VERSION 5.7 ;
  NOWIREEXTENSIONATPIN ON ;
  DIVIDERCHAR "/" ;
  BUSBITCHARS "[]" ;
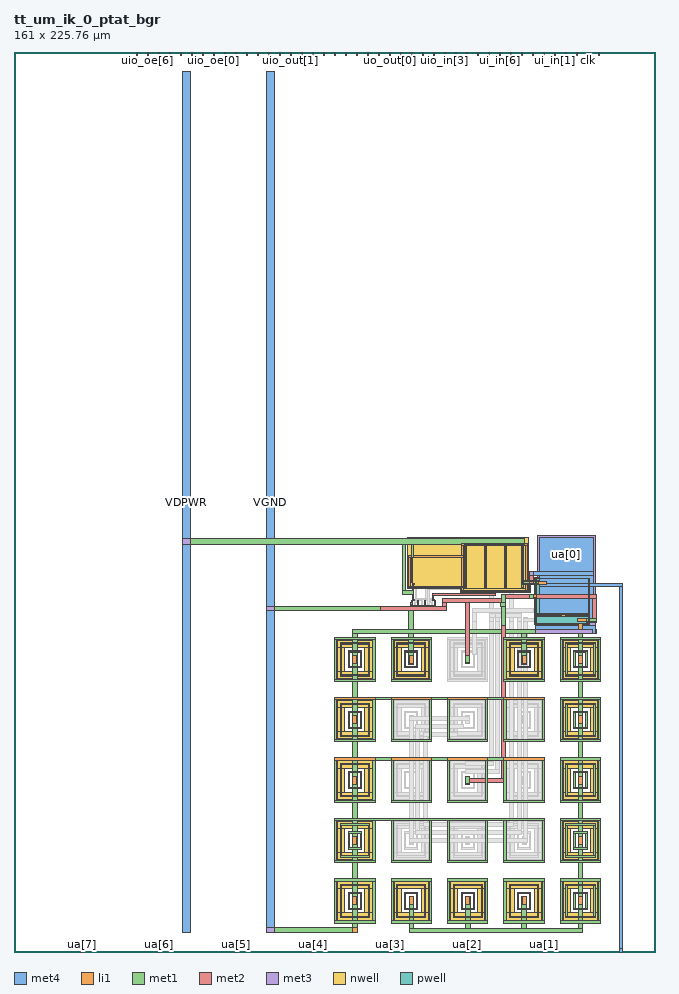
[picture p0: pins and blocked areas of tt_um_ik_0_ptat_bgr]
MACRO tt_um_ik_0_ptat_bgr
  CLASS BLOCK ;
  FOREIGN tt_um_ik_0_ptat_bgr ;
  ORIGIN 0.000 0.000 ;
  SIZE 161.000 BY 225.760 ;
  PIN clk
    DIRECTION INPUT ;
    USE SIGNAL ;
    PORT
      LAYER met4 ;
        RECT 143.830 224.760 144.130 225.760 ;
    END
  END clk
  PIN ena
    DIRECTION INPUT ;
    USE SIGNAL ;
    PORT
      LAYER met4 ;
        RECT 146.590 224.760 146.890 225.760 ;
    END
  END ena
  PIN rst_n
    DIRECTION INPUT ;
    USE SIGNAL ;
    PORT
      LAYER met4 ;
        RECT 141.070 224.760 141.370 225.760 ;
    END
  END rst_n
  PIN ua[0]
    DIRECTION INOUT ;
    USE SIGNAL ;
    ANTENNAGATEAREA 0.500000 ;
    ANTENNADIFFAREA 2.900000 ;
    PORT
      LAYER li1 ;
        RECT 127.530 91.580 127.700 101.620 ;
        RECT 131.540 92.310 133.700 93.000 ;
        RECT 104.890 88.320 105.390 88.490 ;
      LAYER met1 ;
        RECT 127.400 93.300 127.800 101.650 ;
        RECT 129.200 94.350 130.200 95.350 ;
        RECT 127.400 92.950 131.600 93.300 ;
        RECT 127.400 92.360 133.675 92.950 ;
        RECT 127.400 92.300 131.600 92.360 ;
        RECT 127.400 91.550 127.800 92.300 ;
        RECT 104.950 88.520 105.350 89.100 ;
        RECT 104.910 88.290 105.370 88.520 ;
      LAYER met2 ;
        RECT 129.200 92.300 130.200 95.350 ;
        RECT 129.200 90.550 129.600 92.300 ;
        RECT 120.350 90.150 129.600 90.550 ;
        RECT 120.350 89.900 120.750 90.150 ;
        RECT 104.950 89.500 120.750 89.900 ;
        RECT 104.950 88.600 105.350 89.500 ;
      LAYER met3 ;
        RECT 129.200 94.350 130.200 95.350 ;
      LAYER met4 ;
        RECT 131.745 95.350 145.355 103.965 ;
        RECT 129.200 94.350 145.355 95.350 ;
        RECT 131.745 92.500 145.355 94.350 ;
        RECT 131.745 91.600 152.700 92.500 ;
        RECT 131.745 83.355 145.355 91.600 ;
        RECT 151.800 1.000 152.700 91.600 ;
        RECT 151.800 0.000 152.710 1.000 ;
    END
  END ua[0]
  PIN ua[1]
    DIRECTION INOUT ;
    USE SIGNAL ;
    PORT
      LAYER met4 ;
        RECT 132.490 0.000 133.390 1.000 ;
    END
  END ua[1]
  PIN ua[2]
    DIRECTION INOUT ;
    USE SIGNAL ;
    PORT
      LAYER met4 ;
        RECT 113.170 0.000 114.070 1.000 ;
    END
  END ua[2]
  PIN ua[3]
    DIRECTION INOUT ;
    USE SIGNAL ;
    PORT
      LAYER met4 ;
        RECT 93.850 0.000 94.750 1.000 ;
    END
  END ua[3]
  PIN ua[4]
    DIRECTION INOUT ;
    USE SIGNAL ;
    PORT
      LAYER met4 ;
        RECT 74.530 0.000 75.430 1.000 ;
    END
  END ua[4]
  PIN ua[5]
    DIRECTION INOUT ;
    USE SIGNAL ;
    PORT
      LAYER met4 ;
        RECT 55.210 0.000 56.110 1.000 ;
    END
  END ua[5]
  PIN ua[6]
    DIRECTION INOUT ;
    USE SIGNAL ;
    PORT
      LAYER met4 ;
        RECT 35.890 0.000 36.790 1.000 ;
    END
  END ua[6]
  PIN ua[7]
    DIRECTION INOUT ;
    USE SIGNAL ;
    PORT
      LAYER met4 ;
        RECT 16.570 0.000 17.470 1.000 ;
    END
  END ua[7]
  PIN ui_in[0]
    DIRECTION INPUT ;
    USE SIGNAL ;
    PORT
      LAYER met4 ;
        RECT 138.310 224.760 138.610 225.760 ;
    END
  END ui_in[0]
  PIN ui_in[1]
    DIRECTION INPUT ;
    USE SIGNAL ;
    PORT
      LAYER met4 ;
        RECT 135.550 224.760 135.850 225.760 ;
    END
  END ui_in[1]
  PIN ui_in[2]
    DIRECTION INPUT ;
    USE SIGNAL ;
    PORT
      LAYER met4 ;
        RECT 132.790 224.760 133.090 225.760 ;
    END
  END ui_in[2]
  PIN ui_in[3]
    DIRECTION INPUT ;
    USE SIGNAL ;
    PORT
      LAYER met4 ;
        RECT 130.030 224.760 130.330 225.760 ;
    END
  END ui_in[3]
  PIN ui_in[4]
    DIRECTION INPUT ;
    USE SIGNAL ;
    PORT
      LAYER met4 ;
        RECT 127.270 224.760 127.570 225.760 ;
    END
  END ui_in[4]
  PIN ui_in[5]
    DIRECTION INPUT ;
    USE SIGNAL ;
    PORT
      LAYER met4 ;
        RECT 124.510 224.760 124.810 225.760 ;
    END
  END ui_in[5]
  PIN ui_in[6]
    DIRECTION INPUT ;
    USE SIGNAL ;
    PORT
      LAYER met4 ;
        RECT 121.750 224.760 122.050 225.760 ;
    END
  END ui_in[6]
  PIN ui_in[7]
    DIRECTION INPUT ;
    USE SIGNAL ;
    PORT
      LAYER met4 ;
        RECT 118.990 224.760 119.290 225.760 ;
    END
  END ui_in[7]
  PIN uio_in[0]
    DIRECTION INPUT ;
    USE SIGNAL ;
    PORT
      LAYER met4 ;
        RECT 116.230 224.760 116.530 225.760 ;
    END
  END uio_in[0]
  PIN uio_in[1]
    DIRECTION INPUT ;
    USE SIGNAL ;
    PORT
      LAYER met4 ;
        RECT 113.470 224.760 113.770 225.760 ;
    END
  END uio_in[1]
  PIN uio_in[2]
    DIRECTION INPUT ;
    USE SIGNAL ;
    PORT
      LAYER met4 ;
        RECT 110.710 224.760 111.010 225.760 ;
    END
  END uio_in[2]
  PIN uio_in[3]
    DIRECTION INPUT ;
    USE SIGNAL ;
    PORT
      LAYER met4 ;
        RECT 107.950 224.760 108.250 225.760 ;
    END
  END uio_in[3]
  PIN uio_in[4]
    DIRECTION INPUT ;
    USE SIGNAL ;
    PORT
      LAYER met4 ;
        RECT 105.190 224.760 105.490 225.760 ;
    END
  END uio_in[4]
  PIN uio_in[5]
    DIRECTION INPUT ;
    USE SIGNAL ;
    PORT
      LAYER met4 ;
        RECT 102.430 224.760 102.730 225.760 ;
    END
  END uio_in[5]
  PIN uio_in[6]
    DIRECTION INPUT ;
    USE SIGNAL ;
    PORT
      LAYER met4 ;
        RECT 99.670 224.760 99.970 225.760 ;
    END
  END uio_in[6]
  PIN uio_in[7]
    DIRECTION INPUT ;
    USE SIGNAL ;
    PORT
      LAYER met4 ;
        RECT 96.910 224.760 97.210 225.760 ;
    END
  END uio_in[7]
  PIN uio_oe[0]
    DIRECTION OUTPUT ;
    USE SIGNAL ;
    PORT
      LAYER met4 ;
        RECT 49.990 224.760 50.290 225.760 ;
    END
  END uio_oe[0]
  PIN uio_oe[1]
    DIRECTION OUTPUT ;
    USE SIGNAL ;
    PORT
      LAYER met4 ;
        RECT 47.230 224.760 47.530 225.760 ;
    END
  END uio_oe[1]
  PIN uio_oe[2]
    DIRECTION OUTPUT ;
    USE SIGNAL ;
    PORT
      LAYER met4 ;
        RECT 44.470 224.760 44.770 225.760 ;
    END
  END uio_oe[2]
  PIN uio_oe[3]
    DIRECTION OUTPUT ;
    USE SIGNAL ;
    PORT
      LAYER met4 ;
        RECT 41.710 224.760 42.010 225.760 ;
    END
  END uio_oe[3]
  PIN uio_oe[4]
    DIRECTION OUTPUT ;
    USE SIGNAL ;
    PORT
      LAYER met4 ;
        RECT 38.950 224.760 39.250 225.760 ;
    END
  END uio_oe[4]
  PIN uio_oe[5]
    DIRECTION OUTPUT ;
    USE SIGNAL ;
    PORT
      LAYER met4 ;
        RECT 36.190 224.760 36.490 225.760 ;
    END
  END uio_oe[5]
  PIN uio_oe[6]
    DIRECTION OUTPUT ;
    USE SIGNAL ;
    PORT
      LAYER met4 ;
        RECT 33.430 224.760 33.730 225.760 ;
    END
  END uio_oe[6]
  PIN uio_oe[7]
    DIRECTION OUTPUT ;
    USE SIGNAL ;
    PORT
      LAYER met4 ;
        RECT 30.670 224.760 30.970 225.760 ;
    END
  END uio_oe[7]
  PIN uio_out[0]
    DIRECTION OUTPUT ;
    USE SIGNAL ;
    PORT
      LAYER met4 ;
        RECT 72.070 224.760 72.370 225.760 ;
    END
  END uio_out[0]
  PIN uio_out[1]
    DIRECTION OUTPUT ;
    USE SIGNAL ;
    PORT
      LAYER met4 ;
        RECT 69.310 224.760 69.610 225.760 ;
    END
  END uio_out[1]
  PIN uio_out[2]
    DIRECTION OUTPUT ;
    USE SIGNAL ;
    PORT
      LAYER met4 ;
        RECT 66.550 224.760 66.850 225.760 ;
    END
  END uio_out[2]
  PIN uio_out[3]
    DIRECTION OUTPUT ;
    USE SIGNAL ;
    PORT
      LAYER met4 ;
        RECT 63.790 224.760 64.090 225.760 ;
    END
  END uio_out[3]
  PIN uio_out[4]
    DIRECTION OUTPUT ;
    USE SIGNAL ;
    PORT
      LAYER met4 ;
        RECT 61.030 224.760 61.330 225.760 ;
    END
  END uio_out[4]
  PIN uio_out[5]
    DIRECTION OUTPUT ;
    USE SIGNAL ;
    PORT
      LAYER met4 ;
        RECT 58.270 224.760 58.570 225.760 ;
    END
  END uio_out[5]
  PIN uio_out[6]
    DIRECTION OUTPUT ;
    USE SIGNAL ;
    PORT
      LAYER met4 ;
        RECT 55.510 224.760 55.810 225.760 ;
    END
  END uio_out[6]
  PIN uio_out[7]
    DIRECTION OUTPUT ;
    USE SIGNAL ;
    PORT
      LAYER met4 ;
        RECT 52.750 224.760 53.050 225.760 ;
    END
  END uio_out[7]
  PIN uo_out[0]
    DIRECTION OUTPUT ;
    USE SIGNAL ;
    PORT
      LAYER met4 ;
        RECT 94.150 224.760 94.450 225.760 ;
    END
  END uo_out[0]
  PIN uo_out[1]
    DIRECTION OUTPUT ;
    USE SIGNAL ;
    PORT
      LAYER met4 ;
        RECT 91.390 224.760 91.690 225.760 ;
    END
  END uo_out[1]
  PIN uo_out[2]
    DIRECTION OUTPUT ;
    USE SIGNAL ;
    PORT
      LAYER met4 ;
        RECT 88.630 224.760 88.930 225.760 ;
    END
  END uo_out[2]
  PIN uo_out[3]
    DIRECTION OUTPUT ;
    USE SIGNAL ;
    PORT
      LAYER met4 ;
        RECT 85.870 224.760 86.170 225.760 ;
    END
  END uo_out[3]
  PIN uo_out[4]
    DIRECTION OUTPUT ;
    USE SIGNAL ;
    PORT
      LAYER met4 ;
        RECT 83.110 224.760 83.410 225.760 ;
    END
  END uo_out[4]
  PIN uo_out[5]
    DIRECTION OUTPUT ;
    USE SIGNAL ;
    PORT
      LAYER met4 ;
        RECT 80.350 224.760 80.650 225.760 ;
    END
  END uo_out[5]
  PIN uo_out[6]
    DIRECTION OUTPUT ;
    USE SIGNAL ;
    PORT
      LAYER met4 ;
        RECT 77.590 224.760 77.890 225.760 ;
    END
  END uo_out[6]
  PIN uo_out[7]
    DIRECTION OUTPUT ;
    USE SIGNAL ;
    PORT
      LAYER met4 ;
        RECT 74.830 224.760 75.130 225.760 ;
    END
  END uo_out[7]
  PIN VDPWR
    DIRECTION INOUT ;
    USE POWER ;
    PORT
      LAYER nwell ;
        RECT 98.800 91.100 129.000 104.100 ;
        RECT 112.000 90.100 129.000 91.100 ;
      LAYER li1 ;
        RECT 112.300 102.000 128.700 102.400 ;
        RECT 112.300 99.400 112.700 102.000 ;
        RECT 99.000 99.000 112.700 99.400 ;
        RECT 99.000 91.800 99.400 99.000 ;
        RECT 99.840 97.080 100.010 98.120 ;
        RECT 99.740 92.680 99.910 93.720 ;
        RECT 99.970 92.295 100.470 92.465 ;
        RECT 112.300 91.800 112.700 99.000 ;
        RECT 99.000 91.400 112.700 91.800 ;
        RECT 113.240 91.580 113.410 101.620 ;
        RECT 118.240 91.580 118.410 101.620 ;
        RECT 123.240 91.580 123.410 101.620 ;
        RECT 112.300 90.800 112.700 91.400 ;
        RECT 128.300 90.800 128.700 102.000 ;
        RECT 112.300 90.400 128.700 90.800 ;
        RECT 99.940 88.320 100.440 88.490 ;
      LAYER met1 ;
        RECT 42.200 102.100 128.000 103.600 ;
        RECT 97.400 90.700 98.200 102.100 ;
        RECT 99.600 98.900 100.150 102.100 ;
        RECT 113.000 102.000 128.000 102.100 ;
        RECT 99.700 97.100 100.050 98.900 ;
        RECT 99.700 93.700 99.900 97.100 ;
        RECT 99.700 93.650 99.940 93.700 ;
        RECT 99.710 92.700 99.940 93.650 ;
        RECT 99.990 92.265 100.450 92.495 ;
        RECT 100.000 90.700 100.250 92.265 ;
        RECT 113.100 91.550 113.500 102.000 ;
        RECT 118.100 91.550 118.500 102.000 ;
        RECT 123.100 91.550 123.500 102.000 ;
        RECT 97.400 89.700 100.250 90.700 ;
        RECT 100.000 88.520 100.250 89.700 ;
        RECT 99.960 88.290 100.420 88.520 ;
      LAYER met2 ;
        RECT 42.200 102.100 44.200 103.600 ;
      LAYER met3 ;
        RECT 42.200 102.100 44.200 103.600 ;
      LAYER met4 ;
        RECT 42.200 5.000 44.200 220.760 ;
    END
  END VDPWR
  PIN VGND
    DIRECTION INOUT ;
    USE GROUND ;
    PORT
      LAYER pwell ;
        RECT 130.600 84.400 144.600 94.000 ;
        RECT 130.600 82.100 144.420 84.400 ;
      LAYER nwell ;
        RECT 81.200 76.420 89.820 78.220 ;
        RECT 81.200 70.400 83.000 76.420 ;
        RECT 88.020 70.400 89.820 76.420 ;
        RECT 81.200 68.600 89.820 70.400 ;
        RECT 95.350 76.420 103.970 78.220 ;
        RECT 95.350 70.400 97.150 76.420 ;
        RECT 102.170 70.400 103.970 76.420 ;
        RECT 95.350 68.600 103.970 70.400 ;
        RECT 123.650 76.420 132.270 78.220 ;
        RECT 123.650 70.400 125.450 76.420 ;
        RECT 130.470 70.400 132.270 76.420 ;
        RECT 123.650 68.600 132.270 70.400 ;
        RECT 137.800 76.420 146.420 78.220 ;
        RECT 137.800 70.400 139.600 76.420 ;
        RECT 144.620 70.400 146.420 76.420 ;
        RECT 137.800 68.600 146.420 70.400 ;
        RECT 81.200 61.270 89.820 63.070 ;
        RECT 81.200 55.250 83.000 61.270 ;
        RECT 88.020 55.250 89.820 61.270 ;
        RECT 81.200 53.450 89.820 55.250 ;
        RECT 137.800 61.270 146.420 63.070 ;
        RECT 137.800 55.250 139.600 61.270 ;
        RECT 144.620 55.250 146.420 61.270 ;
        RECT 137.800 53.450 146.420 55.250 ;
        RECT 81.200 46.120 89.820 47.920 ;
        RECT 81.200 40.100 83.000 46.120 ;
        RECT 88.020 40.100 89.820 46.120 ;
        RECT 81.200 38.300 89.820 40.100 ;
        RECT 137.800 46.120 146.420 47.920 ;
        RECT 137.800 40.100 139.600 46.120 ;
        RECT 144.620 40.100 146.420 46.120 ;
        RECT 137.800 38.300 146.420 40.100 ;
        RECT 81.200 30.970 89.820 32.770 ;
        RECT 81.200 24.950 83.000 30.970 ;
        RECT 88.020 24.950 89.820 30.970 ;
        RECT 81.200 23.150 89.820 24.950 ;
        RECT 137.800 30.970 146.420 32.770 ;
        RECT 137.800 24.950 139.600 30.970 ;
        RECT 144.620 24.950 146.420 30.970 ;
        RECT 137.800 23.150 146.420 24.950 ;
        RECT 81.200 15.820 89.820 17.620 ;
        RECT 81.200 9.800 83.000 15.820 ;
        RECT 88.020 9.800 89.820 15.820 ;
        RECT 81.200 8.000 89.820 9.800 ;
        RECT 95.350 15.820 103.970 17.620 ;
        RECT 95.350 9.800 97.150 15.820 ;
        RECT 102.170 9.800 103.970 15.820 ;
        RECT 95.350 8.000 103.970 9.800 ;
        RECT 109.500 15.820 118.120 17.620 ;
        RECT 109.500 9.800 111.300 15.820 ;
        RECT 116.320 9.800 118.120 15.820 ;
        RECT 109.500 8.000 118.120 9.800 ;
        RECT 123.650 15.820 132.270 17.620 ;
        RECT 123.650 9.800 125.450 15.820 ;
        RECT 130.470 9.800 132.270 15.820 ;
        RECT 123.650 8.000 132.270 9.800 ;
        RECT 137.800 15.820 146.420 17.620 ;
        RECT 137.800 9.800 139.600 15.820 ;
        RECT 144.620 9.800 146.420 15.820 ;
        RECT 137.800 8.000 146.420 9.800 ;
      LAYER li1 ;
        RECT 130.800 93.600 144.400 93.800 ;
        RECT 130.800 89.600 131.000 93.600 ;
        RECT 130.400 88.800 131.000 89.600 ;
        RECT 99.710 87.110 99.880 88.150 ;
        RECT 101.360 87.110 101.530 88.150 ;
        RECT 103.010 87.110 103.180 88.150 ;
        RECT 105.450 87.110 105.620 88.150 ;
        RECT 130.800 84.800 131.000 88.800 ;
        RECT 144.200 84.800 144.400 93.600 ;
        RECT 130.800 84.600 144.400 84.800 ;
        RECT 137.300 84.270 138.300 84.600 ;
        RECT 130.780 84.100 144.240 84.270 ;
        RECT 130.780 82.450 130.950 84.100 ;
        RECT 141.430 82.930 143.590 83.620 ;
        RECT 144.070 82.450 144.240 84.100 ;
        RECT 130.780 82.280 144.240 82.450 ;
        RECT 141.600 80.850 142.600 82.280 ;
        RECT 80.400 78.400 90.600 79.000 ;
        RECT 80.400 68.400 81.000 78.400 ;
        RECT 81.830 77.260 89.190 77.590 ;
        RECT 81.830 69.560 82.160 77.260 ;
        RECT 83.840 75.250 87.180 75.580 ;
        RECT 83.840 71.570 84.170 75.250 ;
        RECT 85.005 72.395 86.015 74.425 ;
        RECT 86.850 71.570 87.180 75.250 ;
        RECT 83.840 71.240 87.180 71.570 ;
        RECT 88.860 69.560 89.190 77.260 ;
        RECT 81.830 69.230 89.190 69.560 ;
        RECT 90.000 68.400 90.600 78.400 ;
        RECT 80.400 67.800 90.600 68.400 ;
        RECT 94.600 78.400 104.800 79.000 ;
        RECT 94.600 68.400 95.200 78.400 ;
        RECT 95.980 77.260 103.340 77.590 ;
        RECT 95.980 69.560 96.310 77.260 ;
        RECT 97.990 75.250 101.330 75.580 ;
        RECT 97.990 71.570 98.320 75.250 ;
        RECT 99.155 72.395 100.165 74.425 ;
        RECT 101.000 71.570 101.330 75.250 ;
        RECT 97.990 71.240 101.330 71.570 ;
        RECT 103.010 69.560 103.340 77.260 ;
        RECT 95.980 69.230 103.340 69.560 ;
        RECT 104.200 68.400 104.800 78.400 ;
        RECT 122.900 78.400 133.100 79.000 ;
        RECT 113.305 72.395 114.315 74.425 ;
        RECT 94.600 67.800 104.800 68.400 ;
        RECT 122.900 68.400 123.500 78.400 ;
        RECT 124.280 77.260 131.640 77.590 ;
        RECT 124.280 69.560 124.610 77.260 ;
        RECT 126.290 75.250 129.630 75.580 ;
        RECT 126.290 71.570 126.620 75.250 ;
        RECT 127.455 72.395 128.465 74.425 ;
        RECT 129.300 71.570 129.630 75.250 ;
        RECT 126.290 71.240 129.630 71.570 ;
        RECT 131.310 69.560 131.640 77.260 ;
        RECT 124.280 69.230 131.640 69.560 ;
        RECT 132.500 68.400 133.100 78.400 ;
        RECT 122.900 67.800 133.100 68.400 ;
        RECT 137.000 78.400 147.200 79.000 ;
        RECT 137.000 68.400 137.600 78.400 ;
        RECT 138.430 77.260 145.790 77.590 ;
        RECT 138.430 69.560 138.760 77.260 ;
        RECT 140.440 75.250 143.780 75.580 ;
        RECT 140.440 71.570 140.770 75.250 ;
        RECT 141.605 72.395 142.615 74.425 ;
        RECT 143.450 71.570 143.780 75.250 ;
        RECT 140.440 71.240 143.780 71.570 ;
        RECT 145.460 69.560 145.790 77.260 ;
        RECT 138.430 69.230 145.790 69.560 ;
        RECT 146.600 68.400 147.200 78.400 ;
        RECT 137.000 67.800 147.200 68.400 ;
        RECT 80.400 63.300 90.600 63.900 ;
        RECT 80.400 53.300 81.000 63.300 ;
        RECT 81.830 62.110 89.190 62.440 ;
        RECT 81.830 54.410 82.160 62.110 ;
        RECT 83.840 60.100 87.180 60.430 ;
        RECT 83.840 56.420 84.170 60.100 ;
        RECT 85.005 57.245 86.015 59.275 ;
        RECT 86.850 56.420 87.180 60.100 ;
        RECT 83.840 56.090 87.180 56.420 ;
        RECT 88.860 54.410 89.190 62.110 ;
        RECT 81.830 54.080 89.190 54.410 ;
        RECT 90.000 53.300 90.600 63.300 ;
        RECT 80.400 52.700 90.600 53.300 ;
        RECT 94.600 63.300 104.800 63.900 ;
        RECT 94.600 53.300 95.200 63.300 ;
        RECT 104.200 53.300 104.800 63.300 ;
        RECT 94.600 52.700 104.800 53.300 ;
        RECT 108.700 63.300 118.900 63.900 ;
        RECT 108.700 53.300 109.300 63.300 ;
        RECT 118.300 53.300 118.900 63.300 ;
        RECT 108.700 52.700 118.900 53.300 ;
        RECT 122.900 63.300 133.100 63.900 ;
        RECT 122.900 53.300 123.500 63.300 ;
        RECT 132.500 53.300 133.100 63.300 ;
        RECT 122.900 52.700 133.100 53.300 ;
        RECT 137.000 63.300 147.200 63.900 ;
        RECT 137.000 53.300 137.600 63.300 ;
        RECT 138.430 62.110 145.790 62.440 ;
        RECT 138.430 54.410 138.760 62.110 ;
        RECT 140.440 60.100 143.780 60.430 ;
        RECT 140.440 56.420 140.770 60.100 ;
        RECT 141.605 57.245 142.615 59.275 ;
        RECT 143.450 56.420 143.780 60.100 ;
        RECT 140.440 56.090 143.780 56.420 ;
        RECT 145.460 54.410 145.790 62.110 ;
        RECT 138.430 54.080 145.790 54.410 ;
        RECT 146.600 53.300 147.200 63.300 ;
        RECT 137.000 52.700 147.200 53.300 ;
        RECT 80.400 48.100 90.600 48.700 ;
        RECT 80.400 38.100 81.000 48.100 ;
        RECT 81.830 46.960 89.190 47.290 ;
        RECT 81.830 39.260 82.160 46.960 ;
        RECT 83.840 44.950 87.180 45.280 ;
        RECT 83.840 41.270 84.170 44.950 ;
        RECT 85.005 42.095 86.015 44.125 ;
        RECT 86.850 41.270 87.180 44.950 ;
        RECT 83.840 40.940 87.180 41.270 ;
        RECT 88.860 39.260 89.190 46.960 ;
        RECT 81.830 38.930 89.190 39.260 ;
        RECT 90.000 38.100 90.600 48.100 ;
        RECT 80.400 37.500 90.600 38.100 ;
        RECT 94.600 48.100 104.800 48.700 ;
        RECT 94.600 38.100 95.200 48.100 ;
        RECT 104.200 38.100 104.800 48.100 ;
        RECT 94.600 37.500 104.800 38.100 ;
        RECT 108.700 48.100 118.900 48.700 ;
        RECT 108.700 38.100 109.300 48.100 ;
        RECT 113.305 42.095 114.315 44.125 ;
        RECT 118.300 38.100 118.900 48.100 ;
        RECT 108.700 37.500 118.900 38.100 ;
        RECT 122.900 48.100 133.100 48.700 ;
        RECT 122.900 38.100 123.500 48.100 ;
        RECT 132.500 38.100 133.100 48.100 ;
        RECT 122.900 37.500 133.100 38.100 ;
        RECT 137.000 48.100 147.200 48.700 ;
        RECT 137.000 38.100 137.600 48.100 ;
        RECT 138.430 46.960 145.790 47.290 ;
        RECT 138.430 39.260 138.760 46.960 ;
        RECT 140.440 44.950 143.780 45.280 ;
        RECT 140.440 41.270 140.770 44.950 ;
        RECT 141.605 42.095 142.615 44.125 ;
        RECT 143.450 41.270 143.780 44.950 ;
        RECT 140.440 40.940 143.780 41.270 ;
        RECT 145.460 39.260 145.790 46.960 ;
        RECT 138.430 38.930 145.790 39.260 ;
        RECT 146.600 38.100 147.200 48.100 ;
        RECT 137.000 37.500 147.200 38.100 ;
        RECT 80.400 33.000 133.100 33.600 ;
        RECT 80.400 23.000 81.000 33.000 ;
        RECT 81.830 31.810 89.190 32.140 ;
        RECT 81.830 24.110 82.160 31.810 ;
        RECT 83.840 29.800 87.180 30.130 ;
        RECT 83.840 26.120 84.170 29.800 ;
        RECT 85.005 26.945 86.015 28.975 ;
        RECT 86.850 26.120 87.180 29.800 ;
        RECT 83.840 25.790 87.180 26.120 ;
        RECT 88.860 24.110 89.190 31.810 ;
        RECT 81.830 23.780 89.190 24.110 ;
        RECT 90.000 23.000 90.600 33.000 ;
        RECT 80.400 22.400 90.600 23.000 ;
        RECT 94.600 23.000 95.200 33.000 ;
        RECT 104.200 23.000 104.800 33.000 ;
        RECT 94.600 22.400 104.800 23.000 ;
        RECT 108.700 23.000 109.300 33.000 ;
        RECT 118.300 23.000 118.900 33.000 ;
        RECT 108.700 22.400 118.900 23.000 ;
        RECT 122.900 23.000 123.500 33.000 ;
        RECT 132.500 23.000 133.100 33.000 ;
        RECT 122.900 22.400 133.100 23.000 ;
        RECT 137.000 33.000 147.200 33.600 ;
        RECT 137.000 23.000 137.600 33.000 ;
        RECT 138.430 31.810 145.790 32.140 ;
        RECT 138.430 24.110 138.760 31.810 ;
        RECT 140.440 29.800 143.780 30.130 ;
        RECT 140.440 26.120 140.770 29.800 ;
        RECT 141.605 26.945 142.615 28.975 ;
        RECT 143.450 26.120 143.780 29.800 ;
        RECT 140.440 25.790 143.780 26.120 ;
        RECT 145.460 24.110 145.790 31.810 ;
        RECT 138.430 23.780 145.790 24.110 ;
        RECT 146.600 23.000 147.200 33.000 ;
        RECT 137.000 22.400 147.200 23.000 ;
        RECT 80.400 17.800 90.600 18.400 ;
        RECT 80.400 7.800 81.000 17.800 ;
        RECT 81.830 16.660 89.190 16.990 ;
        RECT 81.830 8.960 82.160 16.660 ;
        RECT 83.840 14.650 87.180 14.980 ;
        RECT 83.840 10.970 84.170 14.650 ;
        RECT 85.005 11.795 86.015 13.825 ;
        RECT 86.850 10.970 87.180 14.650 ;
        RECT 83.840 10.640 87.180 10.970 ;
        RECT 88.860 8.960 89.190 16.660 ;
        RECT 81.830 8.630 89.190 8.960 ;
        RECT 90.000 7.800 90.600 17.800 ;
        RECT 80.400 7.200 90.600 7.800 ;
        RECT 94.600 17.800 104.800 18.400 ;
        RECT 94.600 7.800 95.200 17.800 ;
        RECT 95.980 16.660 103.340 16.990 ;
        RECT 95.980 8.960 96.310 16.660 ;
        RECT 97.990 14.650 101.330 14.980 ;
        RECT 97.990 10.970 98.320 14.650 ;
        RECT 99.155 11.795 100.165 13.825 ;
        RECT 101.000 10.970 101.330 14.650 ;
        RECT 97.990 10.640 101.330 10.970 ;
        RECT 103.010 8.960 103.340 16.660 ;
        RECT 95.980 8.630 103.340 8.960 ;
        RECT 104.200 7.800 104.800 17.800 ;
        RECT 94.600 7.200 104.800 7.800 ;
        RECT 108.700 17.800 118.900 18.400 ;
        RECT 108.700 7.800 109.300 17.800 ;
        RECT 110.130 16.660 117.490 16.990 ;
        RECT 110.130 8.960 110.460 16.660 ;
        RECT 112.140 14.650 115.480 14.980 ;
        RECT 112.140 10.970 112.470 14.650 ;
        RECT 113.305 11.795 114.315 13.825 ;
        RECT 115.150 10.970 115.480 14.650 ;
        RECT 112.140 10.640 115.480 10.970 ;
        RECT 117.160 8.960 117.490 16.660 ;
        RECT 110.130 8.630 117.490 8.960 ;
        RECT 118.300 7.800 118.900 17.800 ;
        RECT 108.700 7.200 118.900 7.800 ;
        RECT 122.900 17.800 133.100 18.400 ;
        RECT 122.900 7.800 123.500 17.800 ;
        RECT 124.280 16.660 131.640 16.990 ;
        RECT 124.280 8.960 124.610 16.660 ;
        RECT 126.290 14.650 129.630 14.980 ;
        RECT 126.290 10.970 126.620 14.650 ;
        RECT 127.455 11.795 128.465 13.825 ;
        RECT 129.300 10.970 129.630 14.650 ;
        RECT 126.290 10.640 129.630 10.970 ;
        RECT 131.310 8.960 131.640 16.660 ;
        RECT 124.280 8.630 131.640 8.960 ;
        RECT 132.500 7.800 133.100 17.800 ;
        RECT 122.900 7.200 133.100 7.800 ;
        RECT 137.000 17.800 147.200 18.400 ;
        RECT 137.000 7.800 137.600 17.800 ;
        RECT 138.430 16.660 145.790 16.990 ;
        RECT 138.430 8.960 138.760 16.660 ;
        RECT 140.440 14.650 143.780 14.980 ;
        RECT 140.440 10.970 140.770 14.650 ;
        RECT 141.605 11.795 142.615 13.825 ;
        RECT 143.450 10.970 143.780 14.650 ;
        RECT 140.440 10.640 143.780 10.970 ;
        RECT 145.460 8.960 145.790 16.660 ;
        RECT 138.430 8.630 145.790 8.960 ;
        RECT 146.600 7.800 147.200 17.800 ;
        RECT 137.000 7.200 147.200 7.800 ;
        RECT 84.900 5.000 86.100 6.100 ;
      LAYER met1 ;
        RECT 99.680 87.550 99.910 88.130 ;
        RECT 101.330 87.550 101.560 88.130 ;
        RECT 102.980 87.550 103.210 88.130 ;
        RECT 99.550 87.130 99.910 87.550 ;
        RECT 101.200 87.130 101.560 87.550 ;
        RECT 102.850 87.130 103.210 87.550 ;
        RECT 105.420 87.550 105.650 88.130 ;
        RECT 122.200 87.600 123.200 89.700 ;
        RECT 129.200 88.700 131.000 89.700 ;
        RECT 105.420 87.130 105.800 87.550 ;
        RECT 99.550 86.850 99.800 87.130 ;
        RECT 101.200 86.850 101.450 87.130 ;
        RECT 102.850 86.850 103.100 87.130 ;
        RECT 105.550 86.850 105.800 87.130 ;
        RECT 99.550 86.700 105.800 86.850 ;
        RECT 63.300 85.700 105.800 86.700 ;
        RECT 122.000 86.600 123.200 87.600 ;
        RECT 99.000 81.000 100.250 85.700 ;
        RECT 122.200 81.800 123.200 86.600 ;
        RECT 143.500 83.570 146.150 83.750 ;
        RECT 141.455 82.980 146.150 83.570 ;
        RECT 143.500 82.750 146.150 82.980 ;
        RECT 84.900 80.000 146.150 81.000 ;
        RECT 84.900 79.000 86.100 80.000 ;
        RECT 99.000 79.000 100.250 80.000 ;
        RECT 127.400 79.000 128.600 80.000 ;
        RECT 141.490 79.990 142.700 80.000 ;
        RECT 141.500 79.000 142.700 79.990 ;
        RECT 80.400 78.400 90.600 79.000 ;
        RECT 80.400 68.400 81.000 78.400 ;
        RECT 84.900 77.570 86.100 78.400 ;
        RECT 81.850 77.280 89.170 77.570 ;
        RECT 81.850 69.540 82.140 77.280 ;
        RECT 84.900 75.560 86.100 77.280 ;
        RECT 83.860 75.270 87.160 75.560 ;
        RECT 83.860 71.550 84.150 75.270 ;
        RECT 84.900 71.550 86.100 75.270 ;
        RECT 86.870 71.550 87.160 75.270 ;
        RECT 83.860 71.260 87.160 71.550 ;
        RECT 84.900 69.540 86.100 71.260 ;
        RECT 88.880 69.540 89.170 77.280 ;
        RECT 81.850 69.250 89.170 69.540 ;
        RECT 84.900 68.400 86.100 69.250 ;
        RECT 90.000 68.400 90.600 78.400 ;
        RECT 80.400 67.800 90.600 68.400 ;
        RECT 94.600 78.400 104.800 79.000 ;
        RECT 94.600 68.400 95.200 78.400 ;
        RECT 99.000 77.570 100.250 78.400 ;
        RECT 96.000 77.280 103.320 77.570 ;
        RECT 96.000 69.540 96.290 77.280 ;
        RECT 99.000 75.560 100.250 77.280 ;
        RECT 98.010 75.270 101.310 75.560 ;
        RECT 98.010 71.550 98.300 75.270 ;
        RECT 99.000 72.100 100.250 75.270 ;
        RECT 101.020 71.550 101.310 75.270 ;
        RECT 98.010 71.260 101.310 71.550 ;
        RECT 103.030 69.540 103.320 77.280 ;
        RECT 96.000 69.250 103.320 69.540 ;
        RECT 104.200 68.400 104.800 78.400 ;
        RECT 122.900 78.400 133.100 79.000 ;
        RECT 113.305 72.545 114.315 74.275 ;
        RECT 94.600 67.800 104.800 68.400 ;
        RECT 122.900 68.400 123.500 78.400 ;
        RECT 127.400 77.570 128.600 78.400 ;
        RECT 124.300 77.280 131.620 77.570 ;
        RECT 124.300 69.540 124.590 77.280 ;
        RECT 127.400 75.560 128.600 77.280 ;
        RECT 126.310 75.270 129.610 75.560 ;
        RECT 126.310 71.550 126.600 75.270 ;
        RECT 127.400 72.100 128.600 75.270 ;
        RECT 129.320 71.550 129.610 75.270 ;
        RECT 126.310 71.260 129.610 71.550 ;
        RECT 131.330 69.540 131.620 77.280 ;
        RECT 124.300 69.250 131.620 69.540 ;
        RECT 132.500 68.400 133.100 78.400 ;
        RECT 122.900 67.800 133.100 68.400 ;
        RECT 137.000 78.400 147.200 79.000 ;
        RECT 137.000 68.400 137.600 78.400 ;
        RECT 141.500 77.570 142.700 78.400 ;
        RECT 138.450 77.280 145.770 77.570 ;
        RECT 138.450 69.540 138.740 77.280 ;
        RECT 141.500 75.560 142.700 77.280 ;
        RECT 140.460 75.270 143.760 75.560 ;
        RECT 140.460 71.550 140.750 75.270 ;
        RECT 141.500 71.550 142.700 75.270 ;
        RECT 143.470 71.550 143.760 75.270 ;
        RECT 140.460 71.260 143.760 71.550 ;
        RECT 141.500 69.540 142.700 71.260 ;
        RECT 145.480 69.540 145.770 77.280 ;
        RECT 138.450 69.250 145.770 69.540 ;
        RECT 141.500 68.400 142.700 69.250 ;
        RECT 146.600 68.400 147.200 78.400 ;
        RECT 137.000 67.800 147.200 68.400 ;
        RECT 84.900 63.900 86.100 67.800 ;
        RECT 141.500 63.900 142.700 67.800 ;
        RECT 80.400 63.300 133.100 63.900 ;
        RECT 80.400 53.300 81.000 63.300 ;
        RECT 84.900 62.420 86.100 63.300 ;
        RECT 81.850 62.130 89.170 62.420 ;
        RECT 81.850 54.390 82.140 62.130 ;
        RECT 84.900 60.410 86.100 62.130 ;
        RECT 83.860 60.120 87.160 60.410 ;
        RECT 83.860 56.400 84.150 60.120 ;
        RECT 84.900 56.400 86.100 60.120 ;
        RECT 86.870 56.400 87.160 60.120 ;
        RECT 83.860 56.110 87.160 56.400 ;
        RECT 84.900 54.390 86.100 56.110 ;
        RECT 88.880 54.390 89.170 62.130 ;
        RECT 81.850 54.100 89.170 54.390 ;
        RECT 84.900 53.300 86.100 54.100 ;
        RECT 90.000 53.300 90.600 63.300 ;
        RECT 80.400 52.700 90.600 53.300 ;
        RECT 94.600 53.300 95.200 63.300 ;
        RECT 104.200 53.300 104.800 63.300 ;
        RECT 94.600 52.700 104.800 53.300 ;
        RECT 108.700 53.300 109.300 63.300 ;
        RECT 118.300 53.300 118.900 63.300 ;
        RECT 108.700 52.700 118.900 53.300 ;
        RECT 122.900 53.300 123.500 63.300 ;
        RECT 132.500 53.300 133.100 63.300 ;
        RECT 122.900 52.700 133.100 53.300 ;
        RECT 137.000 63.300 147.200 63.900 ;
        RECT 137.000 53.300 137.600 63.300 ;
        RECT 141.500 62.420 142.700 63.300 ;
        RECT 138.450 62.130 145.770 62.420 ;
        RECT 138.450 54.390 138.740 62.130 ;
        RECT 141.500 60.410 142.700 62.130 ;
        RECT 140.460 60.120 143.760 60.410 ;
        RECT 140.460 56.400 140.750 60.120 ;
        RECT 141.500 56.400 142.700 60.120 ;
        RECT 143.470 56.400 143.760 60.120 ;
        RECT 140.460 56.110 143.760 56.400 ;
        RECT 141.500 54.390 142.700 56.110 ;
        RECT 145.480 54.390 145.770 62.130 ;
        RECT 138.450 54.100 145.770 54.390 ;
        RECT 141.500 53.300 142.700 54.100 ;
        RECT 146.600 53.300 147.200 63.300 ;
        RECT 137.000 52.700 147.200 53.300 ;
        RECT 84.900 48.700 86.100 52.700 ;
        RECT 141.500 48.700 142.700 52.700 ;
        RECT 80.400 48.100 133.100 48.700 ;
        RECT 80.400 38.100 81.000 48.100 ;
        RECT 84.900 47.270 86.100 48.100 ;
        RECT 81.850 46.980 89.170 47.270 ;
        RECT 81.850 39.240 82.140 46.980 ;
        RECT 84.900 45.260 86.100 46.980 ;
        RECT 83.860 44.970 87.160 45.260 ;
        RECT 83.860 41.250 84.150 44.970 ;
        RECT 84.900 41.250 86.100 44.970 ;
        RECT 86.870 41.250 87.160 44.970 ;
        RECT 83.860 40.960 87.160 41.250 ;
        RECT 84.900 39.240 86.100 40.960 ;
        RECT 88.880 39.240 89.170 46.980 ;
        RECT 81.850 38.950 89.170 39.240 ;
        RECT 84.900 38.100 86.100 38.950 ;
        RECT 90.000 38.100 90.600 48.100 ;
        RECT 80.400 37.500 90.600 38.100 ;
        RECT 94.600 38.100 95.200 48.100 ;
        RECT 104.200 38.100 104.800 48.100 ;
        RECT 94.600 37.500 104.800 38.100 ;
        RECT 108.700 38.100 109.300 48.100 ;
        RECT 113.305 42.245 114.315 43.975 ;
        RECT 118.300 38.100 118.900 48.100 ;
        RECT 108.700 37.500 118.900 38.100 ;
        RECT 122.900 38.100 123.500 48.100 ;
        RECT 132.500 38.100 133.100 48.100 ;
        RECT 122.900 37.500 133.100 38.100 ;
        RECT 137.000 48.100 147.200 48.700 ;
        RECT 137.000 38.100 137.600 48.100 ;
        RECT 141.500 47.270 142.700 48.100 ;
        RECT 138.450 46.980 145.770 47.270 ;
        RECT 138.450 39.240 138.740 46.980 ;
        RECT 141.500 45.260 142.700 46.980 ;
        RECT 140.460 44.970 143.760 45.260 ;
        RECT 140.460 41.250 140.750 44.970 ;
        RECT 141.500 41.250 142.700 44.970 ;
        RECT 143.470 41.250 143.760 44.970 ;
        RECT 140.460 40.960 143.760 41.250 ;
        RECT 141.500 39.240 142.700 40.960 ;
        RECT 145.480 39.240 145.770 46.980 ;
        RECT 138.450 38.950 145.770 39.240 ;
        RECT 141.500 38.100 142.700 38.950 ;
        RECT 146.600 38.100 147.200 48.100 ;
        RECT 137.000 37.500 147.200 38.100 ;
        RECT 84.900 33.600 86.100 37.500 ;
        RECT 141.500 33.600 142.700 37.500 ;
        RECT 80.400 33.000 133.100 33.600 ;
        RECT 80.400 23.000 81.000 33.000 ;
        RECT 84.900 32.120 86.100 33.000 ;
        RECT 81.850 31.830 89.170 32.120 ;
        RECT 81.850 24.090 82.140 31.830 ;
        RECT 84.900 30.110 86.100 31.830 ;
        RECT 83.860 29.820 87.160 30.110 ;
        RECT 83.860 26.100 84.150 29.820 ;
        RECT 84.900 26.100 86.100 29.820 ;
        RECT 86.870 26.100 87.160 29.820 ;
        RECT 83.860 25.810 87.160 26.100 ;
        RECT 84.900 24.090 86.100 25.810 ;
        RECT 88.880 24.090 89.170 31.830 ;
        RECT 81.850 23.800 89.170 24.090 ;
        RECT 84.900 23.000 86.100 23.800 ;
        RECT 90.000 23.000 90.600 33.000 ;
        RECT 80.400 22.400 90.600 23.000 ;
        RECT 94.600 23.000 95.200 33.000 ;
        RECT 104.200 23.000 104.800 33.000 ;
        RECT 94.600 22.400 104.800 23.000 ;
        RECT 108.700 23.000 109.300 33.000 ;
        RECT 118.300 23.000 118.900 33.000 ;
        RECT 108.700 22.400 118.900 23.000 ;
        RECT 122.900 23.000 123.500 33.000 ;
        RECT 132.500 23.000 133.100 33.000 ;
        RECT 122.900 22.400 133.100 23.000 ;
        RECT 137.000 33.000 147.200 33.600 ;
        RECT 137.000 23.000 137.600 33.000 ;
        RECT 141.500 32.120 142.700 33.000 ;
        RECT 138.450 31.830 145.770 32.120 ;
        RECT 138.450 24.090 138.740 31.830 ;
        RECT 141.500 30.110 142.700 31.830 ;
        RECT 140.460 29.820 143.760 30.110 ;
        RECT 140.460 26.100 140.750 29.820 ;
        RECT 141.500 26.100 142.700 29.820 ;
        RECT 143.470 26.100 143.760 29.820 ;
        RECT 140.460 25.810 143.760 26.100 ;
        RECT 141.500 24.090 142.700 25.810 ;
        RECT 145.480 24.090 145.770 31.830 ;
        RECT 138.450 23.800 145.770 24.090 ;
        RECT 141.500 23.000 142.700 23.800 ;
        RECT 146.600 23.000 147.200 33.000 ;
        RECT 137.000 22.400 147.200 23.000 ;
        RECT 84.900 18.400 86.100 22.400 ;
        RECT 141.500 18.400 142.700 22.400 ;
        RECT 80.400 17.800 90.600 18.400 ;
        RECT 80.400 7.800 81.000 17.800 ;
        RECT 84.900 16.970 86.100 17.800 ;
        RECT 81.850 16.680 89.170 16.970 ;
        RECT 81.850 8.940 82.140 16.680 ;
        RECT 84.900 14.960 86.100 16.680 ;
        RECT 83.860 14.670 87.160 14.960 ;
        RECT 83.860 10.950 84.150 14.670 ;
        RECT 84.900 10.950 86.100 14.670 ;
        RECT 86.870 10.950 87.160 14.670 ;
        RECT 83.860 10.660 87.160 10.950 ;
        RECT 84.900 8.940 86.100 10.660 ;
        RECT 88.880 8.940 89.170 16.680 ;
        RECT 81.850 8.650 89.170 8.940 ;
        RECT 84.900 7.800 86.100 8.650 ;
        RECT 90.000 7.800 90.600 17.800 ;
        RECT 80.400 7.200 90.600 7.800 ;
        RECT 94.600 17.800 104.800 18.400 ;
        RECT 94.600 7.800 95.200 17.800 ;
        RECT 96.000 16.680 103.320 16.970 ;
        RECT 96.000 8.940 96.290 16.680 ;
        RECT 98.010 14.670 101.310 14.960 ;
        RECT 98.010 10.950 98.300 14.670 ;
        RECT 99.100 10.950 100.300 13.900 ;
        RECT 101.020 10.950 101.310 14.670 ;
        RECT 98.010 10.660 101.310 10.950 ;
        RECT 99.100 8.940 100.300 10.660 ;
        RECT 103.030 8.940 103.320 16.680 ;
        RECT 96.000 8.650 103.320 8.940 ;
        RECT 99.100 7.800 100.300 8.650 ;
        RECT 104.200 7.800 104.800 17.800 ;
        RECT 94.600 7.200 104.800 7.800 ;
        RECT 108.700 17.800 118.900 18.400 ;
        RECT 108.700 7.800 109.300 17.800 ;
        RECT 110.150 16.680 117.470 16.970 ;
        RECT 110.150 8.940 110.440 16.680 ;
        RECT 112.160 14.670 115.460 14.960 ;
        RECT 112.160 10.950 112.450 14.670 ;
        RECT 113.200 10.950 114.400 13.900 ;
        RECT 115.170 10.950 115.460 14.670 ;
        RECT 112.160 10.660 115.460 10.950 ;
        RECT 113.200 8.940 114.400 10.660 ;
        RECT 117.180 8.940 117.470 16.680 ;
        RECT 110.150 8.650 117.470 8.940 ;
        RECT 113.200 7.800 114.400 8.650 ;
        RECT 118.300 7.800 118.900 17.800 ;
        RECT 108.700 7.200 118.900 7.800 ;
        RECT 122.900 17.800 133.100 18.400 ;
        RECT 122.900 7.800 123.500 17.800 ;
        RECT 124.300 16.680 131.620 16.970 ;
        RECT 124.300 8.940 124.590 16.680 ;
        RECT 126.310 14.670 129.610 14.960 ;
        RECT 126.310 10.950 126.600 14.670 ;
        RECT 127.300 10.950 128.500 13.900 ;
        RECT 129.320 10.950 129.610 14.670 ;
        RECT 126.310 10.660 129.610 10.950 ;
        RECT 127.300 8.940 128.500 10.660 ;
        RECT 131.330 8.940 131.620 16.680 ;
        RECT 124.300 8.650 131.620 8.940 ;
        RECT 127.300 7.800 128.500 8.650 ;
        RECT 132.500 7.800 133.100 17.800 ;
        RECT 122.900 7.200 133.100 7.800 ;
        RECT 137.000 17.800 147.200 18.400 ;
        RECT 137.000 7.800 137.600 17.800 ;
        RECT 141.500 16.970 142.700 17.800 ;
        RECT 138.450 16.680 145.770 16.970 ;
        RECT 138.450 8.940 138.740 16.680 ;
        RECT 141.500 14.960 142.700 16.680 ;
        RECT 140.460 14.670 143.760 14.960 ;
        RECT 140.460 10.950 140.750 14.670 ;
        RECT 141.500 10.950 142.700 14.670 ;
        RECT 143.470 10.950 143.760 14.670 ;
        RECT 140.460 10.660 143.760 10.950 ;
        RECT 141.500 8.940 142.700 10.660 ;
        RECT 145.480 8.940 145.770 16.680 ;
        RECT 138.450 8.650 145.770 8.940 ;
        RECT 141.500 7.800 142.700 8.650 ;
        RECT 146.600 7.800 147.200 17.800 ;
        RECT 137.000 7.200 147.200 7.800 ;
        RECT 84.900 6.100 86.100 7.200 ;
        RECT 63.300 5.000 86.100 6.100 ;
        RECT 99.100 6.000 100.300 7.200 ;
        RECT 113.200 6.000 114.400 7.200 ;
        RECT 127.300 6.000 128.500 7.200 ;
        RECT 141.500 6.000 142.700 7.200 ;
        RECT 99.100 5.000 142.700 6.000 ;
      LAYER met2 ;
        RECT 122.200 88.700 146.150 89.700 ;
        RECT 107.600 87.700 123.200 88.700 ;
        RECT 107.600 86.700 108.600 87.700 ;
        RECT 63.300 85.700 65.300 86.700 ;
        RECT 92.000 85.700 108.600 86.700 ;
        RECT 113.300 73.000 114.300 87.700 ;
        RECT 122.200 43.600 123.200 82.800 ;
        RECT 145.150 82.750 146.150 88.700 ;
        RECT 130.800 80.000 145.000 81.000 ;
        RECT 113.300 42.600 123.200 43.600 ;
        RECT 63.300 5.000 65.300 6.100 ;
      LAYER met3 ;
        RECT 63.300 85.700 65.300 86.700 ;
        RECT 131.350 81.500 145.750 104.360 ;
        RECT 130.800 80.000 145.000 81.000 ;
        RECT 63.300 5.000 65.300 6.100 ;
      LAYER met4 ;
        RECT 63.300 5.000 65.300 220.760 ;
        RECT 130.800 80.000 145.750 82.000 ;
    END
  END VGND
  OBS
      LAYER nwell ;
        RECT 109.500 76.420 118.120 78.220 ;
        RECT 109.500 70.400 111.300 76.420 ;
        RECT 116.320 70.400 118.120 76.420 ;
        RECT 109.500 68.600 118.120 70.400 ;
        RECT 95.350 61.270 103.970 63.070 ;
        RECT 95.350 55.250 97.150 61.270 ;
        RECT 102.170 55.250 103.970 61.270 ;
        RECT 95.350 53.450 103.970 55.250 ;
        RECT 109.500 61.270 118.120 63.070 ;
        RECT 109.500 55.250 111.300 61.270 ;
        RECT 116.320 55.250 118.120 61.270 ;
        RECT 109.500 53.450 118.120 55.250 ;
        RECT 123.650 61.270 132.270 63.070 ;
        RECT 123.650 55.250 125.450 61.270 ;
        RECT 130.470 55.250 132.270 61.270 ;
        RECT 123.650 53.450 132.270 55.250 ;
        RECT 95.350 46.120 103.970 47.920 ;
        RECT 95.350 40.100 97.150 46.120 ;
        RECT 102.170 40.100 103.970 46.120 ;
        RECT 95.350 38.300 103.970 40.100 ;
        RECT 109.500 46.120 118.120 47.920 ;
        RECT 109.500 40.100 111.300 46.120 ;
        RECT 116.320 40.100 118.120 46.120 ;
        RECT 109.500 38.300 118.120 40.100 ;
        RECT 123.650 46.120 132.270 47.920 ;
        RECT 123.650 40.100 125.450 46.120 ;
        RECT 130.470 40.100 132.270 46.120 ;
        RECT 123.650 38.300 132.270 40.100 ;
        RECT 95.350 30.970 103.970 32.770 ;
        RECT 95.350 24.950 97.150 30.970 ;
        RECT 102.170 24.950 103.970 30.970 ;
        RECT 95.350 23.150 103.970 24.950 ;
        RECT 109.500 30.970 118.120 32.770 ;
        RECT 109.500 24.950 111.300 30.970 ;
        RECT 116.320 24.950 118.120 30.970 ;
        RECT 109.500 23.150 118.120 24.950 ;
        RECT 123.650 30.970 132.270 32.770 ;
        RECT 123.650 24.950 125.450 30.970 ;
        RECT 130.470 24.950 132.270 30.970 ;
        RECT 123.650 23.150 132.270 24.950 ;
      LAYER li1 ;
        RECT 101.470 98.335 111.470 98.505 ;
        RECT 100.630 97.080 100.800 98.120 ;
        RECT 101.240 97.080 101.410 98.120 ;
        RECT 111.530 97.080 111.700 98.120 ;
        RECT 100.070 96.695 100.570 96.865 ;
        RECT 101.470 96.695 111.470 96.865 ;
        RECT 101.470 96.135 111.470 96.305 ;
        RECT 101.240 94.880 101.410 95.920 ;
        RECT 111.530 94.880 111.700 95.920 ;
        RECT 101.470 94.495 111.470 94.665 ;
        RECT 101.470 93.935 111.470 94.105 ;
        RECT 100.530 92.680 100.700 93.720 ;
        RECT 101.240 92.680 101.410 93.720 ;
        RECT 111.530 92.680 111.700 93.720 ;
        RECT 101.470 92.295 111.470 92.465 ;
        RECT 117.530 91.580 117.700 101.620 ;
        RECT 122.530 91.580 122.700 101.620 ;
        RECT 141.540 92.310 143.700 93.000 ;
        RECT 113.470 91.195 117.470 91.365 ;
        RECT 118.470 91.195 122.470 91.365 ;
        RECT 123.470 91.195 127.470 91.365 ;
        RECT 131.540 91.310 133.700 92.000 ;
        RECT 141.540 91.310 143.700 92.000 ;
        RECT 131.540 90.310 133.700 91.000 ;
        RECT 141.540 90.310 143.700 91.000 ;
        RECT 131.540 89.310 133.700 90.000 ;
        RECT 141.540 89.310 143.700 90.000 ;
        RECT 101.590 88.320 102.090 88.490 ;
        RECT 103.240 88.320 103.740 88.490 ;
        RECT 131.540 88.310 133.700 89.000 ;
        RECT 141.540 88.310 143.700 89.000 ;
        RECT 100.500 87.110 100.670 88.150 ;
        RECT 102.150 87.110 102.320 88.150 ;
        RECT 103.800 87.110 103.970 88.150 ;
        RECT 104.660 87.110 104.830 88.150 ;
        RECT 122.000 86.600 123.000 87.600 ;
        RECT 131.540 87.310 133.700 88.000 ;
        RECT 141.540 87.310 143.700 88.000 ;
        RECT 131.540 86.310 133.700 87.000 ;
        RECT 141.540 86.310 143.700 87.000 ;
        RECT 131.540 85.310 133.700 86.000 ;
        RECT 141.540 85.310 143.700 86.000 ;
        RECT 131.430 82.930 133.590 83.620 ;
        RECT 108.700 78.400 118.900 79.000 ;
        RECT 108.700 68.400 109.300 78.400 ;
        RECT 110.130 77.260 117.490 77.590 ;
        RECT 110.130 69.560 110.460 77.260 ;
        RECT 112.140 75.250 115.480 75.580 ;
        RECT 112.140 71.570 112.470 75.250 ;
        RECT 115.150 71.570 115.480 75.250 ;
        RECT 112.140 71.240 115.480 71.570 ;
        RECT 117.160 69.560 117.490 77.260 ;
        RECT 110.130 69.230 117.490 69.560 ;
        RECT 118.300 68.400 118.900 78.400 ;
        RECT 108.700 67.800 118.900 68.400 ;
        RECT 95.980 62.110 103.340 62.440 ;
        RECT 95.980 54.410 96.310 62.110 ;
        RECT 97.990 60.100 101.330 60.430 ;
        RECT 97.990 56.420 98.320 60.100 ;
        RECT 99.155 57.245 100.165 59.275 ;
        RECT 101.000 56.420 101.330 60.100 ;
        RECT 97.990 56.090 101.330 56.420 ;
        RECT 103.010 54.410 103.340 62.110 ;
        RECT 95.980 54.080 103.340 54.410 ;
        RECT 110.130 62.110 117.490 62.440 ;
        RECT 110.130 54.410 110.460 62.110 ;
        RECT 112.140 60.100 115.480 60.430 ;
        RECT 112.140 56.420 112.470 60.100 ;
        RECT 113.305 57.245 114.315 59.275 ;
        RECT 115.150 56.420 115.480 60.100 ;
        RECT 112.140 56.090 115.480 56.420 ;
        RECT 117.160 54.410 117.490 62.110 ;
        RECT 110.130 54.080 117.490 54.410 ;
        RECT 124.280 62.110 131.640 62.440 ;
        RECT 124.280 54.410 124.610 62.110 ;
        RECT 126.290 60.100 129.630 60.430 ;
        RECT 126.290 56.420 126.620 60.100 ;
        RECT 127.455 57.245 128.465 59.275 ;
        RECT 129.300 56.420 129.630 60.100 ;
        RECT 126.290 56.090 129.630 56.420 ;
        RECT 131.310 54.410 131.640 62.110 ;
        RECT 124.280 54.080 131.640 54.410 ;
        RECT 95.980 46.960 103.340 47.290 ;
        RECT 95.980 39.260 96.310 46.960 ;
        RECT 97.990 44.950 101.330 45.280 ;
        RECT 97.990 41.270 98.320 44.950 ;
        RECT 99.155 42.095 100.165 44.125 ;
        RECT 101.000 41.270 101.330 44.950 ;
        RECT 97.990 40.940 101.330 41.270 ;
        RECT 103.010 39.260 103.340 46.960 ;
        RECT 95.980 38.930 103.340 39.260 ;
        RECT 110.130 46.960 117.490 47.290 ;
        RECT 110.130 39.260 110.460 46.960 ;
        RECT 112.140 44.950 115.480 45.280 ;
        RECT 112.140 41.270 112.470 44.950 ;
        RECT 115.150 41.270 115.480 44.950 ;
        RECT 112.140 40.940 115.480 41.270 ;
        RECT 117.160 39.260 117.490 46.960 ;
        RECT 110.130 38.930 117.490 39.260 ;
        RECT 124.280 46.960 131.640 47.290 ;
        RECT 124.280 39.260 124.610 46.960 ;
        RECT 126.290 44.950 129.630 45.280 ;
        RECT 126.290 41.270 126.620 44.950 ;
        RECT 127.455 42.095 128.465 44.125 ;
        RECT 129.300 41.270 129.630 44.950 ;
        RECT 126.290 40.940 129.630 41.270 ;
        RECT 131.310 39.260 131.640 46.960 ;
        RECT 124.280 38.930 131.640 39.260 ;
        RECT 95.980 31.810 103.340 32.140 ;
        RECT 95.980 24.110 96.310 31.810 ;
        RECT 97.990 29.800 101.330 30.130 ;
        RECT 97.990 26.120 98.320 29.800 ;
        RECT 99.155 26.945 100.165 28.975 ;
        RECT 101.000 26.120 101.330 29.800 ;
        RECT 97.990 25.790 101.330 26.120 ;
        RECT 103.010 24.110 103.340 31.810 ;
        RECT 95.980 23.780 103.340 24.110 ;
        RECT 110.130 31.810 117.490 32.140 ;
        RECT 110.130 24.110 110.460 31.810 ;
        RECT 112.140 29.800 115.480 30.130 ;
        RECT 112.140 26.120 112.470 29.800 ;
        RECT 113.305 26.945 114.315 28.975 ;
        RECT 115.150 26.120 115.480 29.800 ;
        RECT 112.140 25.790 115.480 26.120 ;
        RECT 117.160 24.110 117.490 31.810 ;
        RECT 110.130 23.780 117.490 24.110 ;
        RECT 124.280 31.810 131.640 32.140 ;
        RECT 124.280 24.110 124.610 31.810 ;
        RECT 126.290 29.800 129.630 30.130 ;
        RECT 126.290 26.120 126.620 29.800 ;
        RECT 127.455 26.945 128.465 28.975 ;
        RECT 129.300 26.120 129.630 29.800 ;
        RECT 126.290 25.790 129.630 26.120 ;
        RECT 131.310 24.110 131.640 31.810 ;
        RECT 124.280 23.780 131.640 24.110 ;
      LAYER met1 ;
        RECT 101.490 98.305 111.450 98.535 ;
        RECT 100.600 97.100 101.440 98.100 ;
        RECT 106.200 96.895 106.700 98.305 ;
        RECT 111.500 97.100 112.000 98.100 ;
        RECT 100.090 96.850 100.550 96.895 ;
        RECT 100.090 96.665 100.750 96.850 ;
        RECT 101.490 96.665 111.450 96.895 ;
        RECT 100.500 93.400 100.750 96.665 ;
        RECT 106.200 96.335 106.700 96.665 ;
        RECT 101.490 96.105 111.450 96.335 ;
        RECT 101.000 94.900 101.440 95.900 ;
        RECT 101.000 93.700 101.300 94.900 ;
        RECT 106.200 94.695 106.700 96.105 ;
        RECT 111.700 95.900 112.000 97.100 ;
        RECT 111.500 94.900 112.000 95.900 ;
        RECT 101.490 94.465 111.450 94.695 ;
        RECT 106.200 94.135 106.700 94.465 ;
        RECT 101.490 93.905 111.450 94.135 ;
        RECT 100.500 93.000 100.730 93.400 ;
        RECT 100.500 92.700 100.850 93.000 ;
        RECT 101.000 92.700 101.440 93.700 ;
        RECT 106.200 93.300 106.700 93.905 ;
        RECT 111.500 93.300 111.730 93.700 ;
        RECT 106.200 93.100 111.730 93.300 ;
        RECT 100.650 88.550 100.850 92.700 ;
        RECT 106.200 92.495 106.700 93.100 ;
        RECT 111.500 92.700 111.730 93.100 ;
        RECT 101.490 92.265 111.450 92.495 ;
        RECT 103.210 88.550 103.690 92.265 ;
        RECT 117.400 91.550 117.800 101.650 ;
        RECT 122.400 91.400 122.800 101.650 ;
        RECT 141.565 92.360 143.670 92.950 ;
        RECT 142.400 91.950 143.400 92.360 ;
        RECT 112.750 91.100 128.000 91.400 ;
        RECT 131.570 91.360 133.675 91.950 ;
        RECT 141.565 91.360 143.670 91.950 ;
        RECT 112.750 90.850 113.350 91.100 ;
        RECT 117.400 90.300 120.200 90.950 ;
        RECT 100.650 88.520 102.050 88.550 ;
        RECT 100.650 88.300 102.070 88.520 ;
        RECT 100.650 88.130 100.850 88.300 ;
        RECT 101.610 88.290 102.070 88.300 ;
        RECT 102.300 88.300 104.750 88.550 ;
        RECT 102.300 88.150 102.550 88.300 ;
        RECT 103.260 88.290 103.720 88.300 ;
        RECT 102.150 88.130 102.550 88.150 ;
        RECT 104.500 88.130 104.750 88.300 ;
        RECT 100.470 87.700 100.850 88.130 ;
        RECT 102.120 87.700 102.550 88.130 ;
        RECT 103.770 88.100 104.000 88.130 ;
        RECT 100.470 87.130 100.700 87.700 ;
        RECT 102.120 87.130 102.350 87.700 ;
        RECT 103.770 87.200 104.300 88.100 ;
        RECT 104.500 87.700 104.860 88.130 ;
        RECT 103.770 87.130 104.000 87.200 ;
        RECT 104.630 87.130 104.860 87.700 ;
        RECT 115.000 81.800 116.000 86.100 ;
        RECT 119.200 84.800 120.200 90.300 ;
        RECT 119.200 83.800 121.700 84.800 ;
        RECT 119.200 81.800 120.200 83.800 ;
        RECT 120.700 81.800 121.700 83.800 ;
        RECT 124.200 81.800 125.200 91.100 ;
        RECT 131.900 90.950 132.900 91.360 ;
        RECT 131.570 90.360 133.675 90.950 ;
        RECT 141.565 90.360 143.670 90.950 ;
        RECT 142.400 89.950 143.400 90.360 ;
        RECT 131.570 89.360 133.675 89.950 ;
        RECT 141.565 89.360 143.670 89.950 ;
        RECT 131.900 88.950 132.900 89.360 ;
        RECT 131.570 88.360 133.675 88.950 ;
        RECT 141.565 88.360 143.670 88.950 ;
        RECT 142.400 87.950 143.400 88.360 ;
        RECT 131.570 87.360 133.675 87.950 ;
        RECT 141.565 87.360 143.670 87.950 ;
        RECT 131.900 86.950 132.900 87.360 ;
        RECT 131.570 86.360 133.675 86.950 ;
        RECT 141.565 86.360 143.670 86.950 ;
        RECT 129.200 85.950 131.600 86.100 ;
        RECT 142.400 85.950 143.400 86.360 ;
        RECT 129.200 85.360 133.675 85.950 ;
        RECT 141.565 85.360 143.670 85.950 ;
        RECT 129.200 85.100 131.600 85.360 ;
        RECT 126.200 81.800 127.200 84.800 ;
        RECT 127.700 83.700 128.700 83.800 ;
        RECT 127.700 83.570 131.600 83.700 ;
        RECT 127.700 82.980 133.565 83.570 ;
        RECT 127.700 82.800 131.600 82.980 ;
        RECT 127.700 81.800 128.700 82.800 ;
        RECT 108.700 78.400 118.900 79.000 ;
        RECT 108.700 68.400 109.300 78.400 ;
        RECT 115.000 77.570 116.000 77.900 ;
        RECT 110.150 77.280 117.470 77.570 ;
        RECT 110.150 69.540 110.440 77.280 ;
        RECT 115.000 76.900 116.000 77.280 ;
        RECT 115.000 75.560 116.000 75.700 ;
        RECT 112.160 75.270 116.000 75.560 ;
        RECT 112.160 71.550 112.450 75.270 ;
        RECT 115.000 74.700 116.000 75.270 ;
        RECT 115.170 71.550 115.460 74.700 ;
        RECT 112.160 71.260 115.460 71.550 ;
        RECT 117.180 69.540 117.470 77.280 ;
        RECT 110.150 69.250 117.470 69.540 ;
        RECT 118.300 68.400 118.900 78.400 ;
        RECT 108.700 67.800 118.900 68.400 ;
        RECT 96.000 62.130 103.320 62.420 ;
        RECT 96.000 54.390 96.290 62.130 ;
        RECT 98.010 60.120 101.310 60.410 ;
        RECT 98.010 56.400 98.300 60.120 ;
        RECT 99.155 59.000 100.165 59.125 ;
        RECT 99.155 58.000 100.200 59.000 ;
        RECT 99.155 57.395 100.165 58.000 ;
        RECT 101.020 57.000 101.310 60.120 ;
        RECT 100.700 56.400 101.700 57.000 ;
        RECT 98.010 56.110 101.700 56.400 ;
        RECT 100.700 56.000 101.700 56.110 ;
        RECT 103.030 55.000 103.320 62.130 ;
        RECT 110.150 62.130 117.470 62.420 ;
        RECT 110.150 55.000 110.440 62.130 ;
        RECT 112.160 60.120 115.460 60.410 ;
        RECT 112.160 57.000 112.450 60.120 ;
        RECT 113.305 59.000 114.315 59.125 ;
        RECT 113.200 58.000 114.315 59.000 ;
        RECT 113.305 57.395 114.315 58.000 ;
        RECT 111.700 56.400 112.700 57.000 ;
        RECT 115.170 56.400 115.460 60.120 ;
        RECT 111.700 56.110 115.460 56.400 ;
        RECT 111.700 56.000 112.700 56.110 ;
        RECT 102.700 54.390 103.700 55.000 ;
        RECT 96.000 54.100 103.700 54.390 ;
        RECT 110.150 54.390 111.200 55.000 ;
        RECT 117.180 54.390 117.470 62.130 ;
        RECT 124.300 62.130 131.620 62.420 ;
        RECT 124.300 55.000 124.590 62.130 ;
        RECT 126.310 60.120 129.610 60.410 ;
        RECT 126.310 57.000 126.600 60.120 ;
        RECT 127.455 59.000 128.465 59.125 ;
        RECT 127.455 58.000 128.700 59.000 ;
        RECT 127.455 57.395 128.465 58.000 ;
        RECT 126.200 56.400 127.200 57.000 ;
        RECT 129.320 56.400 129.610 60.120 ;
        RECT 126.200 56.110 129.610 56.400 ;
        RECT 126.200 56.000 127.200 56.110 ;
        RECT 110.150 54.100 117.470 54.390 ;
        RECT 124.200 54.390 125.200 55.000 ;
        RECT 131.330 54.390 131.620 62.130 ;
        RECT 124.200 54.100 131.620 54.390 ;
        RECT 102.700 54.000 103.700 54.100 ;
        RECT 110.200 54.000 111.200 54.100 ;
        RECT 124.200 54.000 125.200 54.100 ;
        RECT 113.300 47.270 114.300 47.800 ;
        RECT 96.000 46.980 103.320 47.270 ;
        RECT 96.000 39.240 96.290 46.980 ;
        RECT 98.010 44.970 101.310 45.260 ;
        RECT 98.010 41.250 98.300 44.970 ;
        RECT 99.155 43.600 100.165 43.975 ;
        RECT 101.020 43.600 101.310 44.970 ;
        RECT 103.030 43.600 103.320 46.980 ;
        RECT 110.150 46.980 117.470 47.270 ;
        RECT 99.155 42.600 100.200 43.600 ;
        RECT 100.700 42.600 101.700 43.600 ;
        RECT 102.700 42.600 103.700 43.600 ;
        RECT 99.155 42.245 100.165 42.600 ;
        RECT 101.020 41.250 101.310 42.600 ;
        RECT 98.010 40.960 101.310 41.250 ;
        RECT 103.030 39.240 103.320 42.600 ;
        RECT 96.000 38.950 103.320 39.240 ;
        RECT 110.150 39.240 110.440 46.980 ;
        RECT 113.300 46.800 114.300 46.980 ;
        RECT 113.300 45.260 114.300 45.800 ;
        RECT 112.160 44.970 115.460 45.260 ;
        RECT 112.160 41.250 112.450 44.970 ;
        RECT 113.300 44.800 114.300 44.970 ;
        RECT 115.170 41.250 115.460 44.970 ;
        RECT 112.160 40.960 115.460 41.250 ;
        RECT 117.180 39.240 117.470 46.980 ;
        RECT 124.300 46.980 131.620 47.270 ;
        RECT 124.300 43.500 124.590 46.980 ;
        RECT 126.310 44.970 129.610 45.260 ;
        RECT 126.310 43.500 126.600 44.970 ;
        RECT 127.455 43.500 128.465 43.975 ;
        RECT 124.200 42.500 125.200 43.500 ;
        RECT 126.200 42.500 127.200 43.500 ;
        RECT 127.455 42.500 128.700 43.500 ;
        RECT 110.150 38.950 117.470 39.240 ;
        RECT 124.300 39.240 124.590 42.500 ;
        RECT 126.310 41.250 126.600 42.500 ;
        RECT 127.455 42.245 128.465 42.500 ;
        RECT 129.320 41.250 129.610 44.970 ;
        RECT 126.310 40.960 129.610 41.250 ;
        RECT 131.330 39.240 131.620 46.980 ;
        RECT 124.300 38.950 131.620 39.240 ;
        RECT 102.700 32.120 103.700 32.500 ;
        RECT 113.400 32.120 114.400 32.500 ;
        RECT 124.200 32.120 125.200 32.500 ;
        RECT 96.000 31.830 103.700 32.120 ;
        RECT 96.000 24.090 96.290 31.830 ;
        RECT 102.700 31.500 103.700 31.830 ;
        RECT 110.150 31.830 117.470 32.120 ;
        RECT 100.700 30.110 101.700 30.500 ;
        RECT 98.010 29.820 101.700 30.110 ;
        RECT 98.010 26.100 98.300 29.820 ;
        RECT 100.700 29.500 101.700 29.820 ;
        RECT 99.155 28.500 100.165 28.825 ;
        RECT 99.155 27.500 100.200 28.500 ;
        RECT 99.155 27.095 100.165 27.500 ;
        RECT 101.020 26.100 101.310 29.500 ;
        RECT 98.010 25.810 101.310 26.100 ;
        RECT 103.030 24.090 103.320 31.500 ;
        RECT 96.000 23.800 103.320 24.090 ;
        RECT 110.150 24.090 110.440 31.830 ;
        RECT 113.400 31.500 114.400 31.830 ;
        RECT 113.300 30.110 114.300 30.500 ;
        RECT 112.160 29.820 115.460 30.110 ;
        RECT 112.160 26.100 112.450 29.820 ;
        RECT 113.300 29.500 114.300 29.820 ;
        RECT 113.305 28.500 114.315 28.825 ;
        RECT 113.300 27.500 114.315 28.500 ;
        RECT 113.305 27.095 114.315 27.500 ;
        RECT 115.170 26.100 115.460 29.820 ;
        RECT 112.160 25.810 115.460 26.100 ;
        RECT 117.180 24.090 117.470 31.830 ;
        RECT 124.200 31.830 131.620 32.120 ;
        RECT 124.200 31.500 125.200 31.830 ;
        RECT 110.150 23.800 117.470 24.090 ;
        RECT 124.300 24.090 124.590 31.500 ;
        RECT 126.200 30.110 127.200 30.500 ;
        RECT 126.200 29.820 129.610 30.110 ;
        RECT 126.200 29.500 127.200 29.820 ;
        RECT 126.310 26.100 126.600 29.500 ;
        RECT 127.455 28.500 128.465 28.825 ;
        RECT 127.455 27.500 128.700 28.500 ;
        RECT 127.455 27.095 128.465 27.500 ;
        RECT 129.320 26.100 129.610 29.820 ;
        RECT 126.310 25.810 129.610 26.100 ;
        RECT 131.330 24.090 131.620 31.830 ;
        RECT 124.300 23.800 131.620 24.090 ;
      LAYER met2 ;
        RECT 103.750 90.850 113.350 91.400 ;
        RECT 103.750 87.200 104.300 90.850 ;
        RECT 117.400 90.300 117.800 92.200 ;
        RECT 115.000 85.100 130.200 86.100 ;
        RECT 120.700 83.800 127.200 84.800 ;
        RECT 115.000 74.700 116.000 82.800 ;
        RECT 99.200 58.000 114.200 59.000 ;
        RECT 99.200 28.500 100.200 58.000 ;
        RECT 100.700 56.000 112.700 57.000 ;
        RECT 100.700 30.500 101.700 56.000 ;
        RECT 102.700 54.000 111.200 55.000 ;
        RECT 102.700 32.500 103.700 54.000 ;
        RECT 119.200 47.800 120.200 82.800 ;
        RECT 113.300 46.800 120.200 47.800 ;
        RECT 120.700 45.800 121.700 82.800 ;
        RECT 113.300 44.800 121.700 45.800 ;
        RECT 124.200 32.500 125.200 82.800 ;
        RECT 102.700 31.500 125.200 32.500 ;
        RECT 126.200 30.500 127.200 82.800 ;
        RECT 100.700 29.500 127.200 30.500 ;
        RECT 127.700 28.500 128.700 82.800 ;
        RECT 99.200 27.500 128.700 28.500 ;
  END
END tt_um_ik_0_ptat_bgr
END LIBRARY

